VERSION 5.5 ;
NAMESCASESENSITIVE ON ;
BUSBITCHARS "[]" ;
DIVIDERCHAR "/" ;

PROPERTYDEFINITIONS
  LAYER routingPitch REAL ;
END PROPERTYDEFINITIONS

UNITS
  DATABASE MICRONS 1000 ;
END UNITS
MANUFACTURINGGRID 0.01 ;
LAYER POLY1
  TYPE MASTERSLICE ;
END POLY1

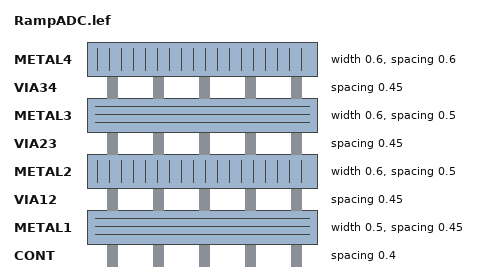
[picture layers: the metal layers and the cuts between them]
LAYER CONT
  TYPE CUT ;
  SPACING 0.4 ;
END CONT

LAYER METAL1
  TYPE ROUTING ;
  DIRECTION HORIZONTAL ;
  PITCH 0 ;
  WIDTH 0.5 ;
  SPACING 0.45 ;
  PROPERTY routingPitch 1.25 ;
END METAL1

LAYER VIA12
  TYPE CUT ;
  SPACING 0.45 ;
END VIA12

LAYER METAL2
  TYPE ROUTING ;
  DIRECTION VERTICAL ;
  PITCH 0 ;
  WIDTH 0.6 ;
  SPACING 0.5 ;
  PROPERTY routingPitch 1.4 ;
END METAL2

LAYER VIA23
  TYPE CUT ;
  SPACING 0.45 ;
END VIA23

LAYER METAL3
  TYPE ROUTING ;
  DIRECTION HORIZONTAL ;
  PITCH 0 ;
  WIDTH 0.6 ;
  SPACING 0.5 ;
  PROPERTY routingPitch 1.25 ;
END METAL3

LAYER VIA34
  TYPE CUT ;
  SPACING 0.45 ;
END VIA34

LAYER METAL4
  TYPE ROUTING ;
  DIRECTION VERTICAL ;
  PITCH 0 ;
  WIDTH 0.6 ;
  SPACING 0.6 ;
  PROPERTY routingPitch 1.4 ;
END METAL4

LAYER OVERLAP
  TYPE OVERLAP ;
END OVERLAP

VIARULE M4_M3 GENERATE
  LAYER METAL3 ;
    ENCLOSURE 0.2 0.2 ;
  LAYER METAL4 ;
    ENCLOSURE 0.15 0.15 ;
  LAYER VIA34 ;
    RECT -0.25 -0.25 0.25 0.25 ;
    SPACING 1 BY 1 ;
END M4_M3

VIARULE M3_M2 GENERATE
  LAYER METAL2 ;
    ENCLOSURE 0.2 0.2 ;
  LAYER METAL3 ;
    ENCLOSURE 0.15 0.15 ;
  LAYER VIA23 ;
    RECT -0.25 -0.25 0.25 0.25 ;
    SPACING 1 BY 1 ;
END M3_M2

VIARULE M2_M1 GENERATE
  LAYER METAL1 ;
    ENCLOSURE 0.2 0.2 ;
  LAYER METAL2 ;
    ENCLOSURE 0.15 0.15 ;
  LAYER VIA12 ;
    RECT -0.25 -0.25 0.25 0.25 ;
    SPACING 1 BY 1 ;
END M2_M1

VIARULE M1_POLY1 GENERATE
  LAYER POLY1 ;
    ENCLOSURE 0.2 0.2 ;
  LAYER METAL1 ;
    ENCLOSURE 0.15 0.15 ;
  LAYER CONT ;
    RECT -0.2 -0.2 0.2 0.2 ;
    SPACING 1 BY 1 ;
END M1_POLY1

VIA M1_POLY1
  LAYER CONT ;
    RECT -0.2 -0.2 0.2 0.2 ;
  LAYER POLY1 ;
    RECT -0.4 -0.4 0.4 0.4 ;
  LAYER METAL1 ;
    RECT -0.35 -0.35 0.35 0.35 ;
END M1_POLY1

VIA M2_M1
  LAYER VIA12 ;
    RECT -0.25 -0.25 0.25 0.25 ;
  LAYER METAL2 ;
    RECT -0.4 -0.4 0.4 0.4 ;
  LAYER METAL1 ;
    RECT -0.45 -0.45 0.45 0.45 ;
END M2_M1

VIA M3_M2
  LAYER VIA23 ;
    RECT -0.25 -0.25 0.25 0.25 ;
  LAYER METAL3 ;
    RECT -0.4 -0.4 0.4 0.4 ;
  LAYER METAL2 ;
    RECT -0.45 -0.45 0.45 0.45 ;
END M3_M2

VIA M4_M3
  LAYER VIA34 ;
    RECT -0.25 -0.25 0.25 0.25 ;
  LAYER METAL4 ;
    RECT -0.4 -0.4 0.4 0.4 ;
  LAYER METAL3 ;
    RECT -0.45 -0.45 0.45 0.45 ;
END M4_M3


MACRO TSMC350nm_Amplifier9T_FGBias
  PIN VD_P
    DIRECTION INOUT ;
    USE SIGNAL ;
    PORT
      LAYER METAL1 ;
        RECT 0.0 16.87 1.4 18.27 ;
    END
  END VD_P
  PIN Vout
    DIRECTION INOUT ;
    USE SIGNAL ;
    PORT
      LAYER METAL1 ;
        RECT 58.96 1.09 60.36 2.49 ;
    END
  END Vout
  PIN VIN_PLUS
    DIRECTION INOUT ;
    USE SIGNAL ;
    PORT
      LAYER METAL1 ;
        RECT 0.0 2.76 1.4 4.16 ;
    END
  END VIN_PLUS
  PIN VD_R
    DIRECTION INOUT ;
    USE SIGNAL ;
    PORT
      LAYER METAL1 ;
        RECT 0.0 11.17 1.4 12.57 ;
    END
  END VD_R
  PIN VIN_MINUS
    DIRECTION INOUT ;
    USE SIGNAL ;
    PORT
      LAYER METAL1 ;
        RECT 0.0 6.97 1.4 8.37 ;
    END
  END VIN_MINUS
  PIN GND_b
    DIRECTION INOUT ;
    USE SIGNAL ;
    PORT
      LAYER METAL2 ;
        RECT 51.59 0.0 52.99 1.4 ;
    END
  END GND_b
  PIN VPWR
    DIRECTION INOUT ;
    USE SIGNAL ;
    PORT
      LAYER METAL2 ;
        RECT 42.13 20.61 43.53 22.0 ;
    END
  END VPWR
  PIN Vsel_b
    DIRECTION INOUT ;
    USE SIGNAL ;
    PORT
      LAYER METAL2 ;
        RECT 0.66 0.0 2.06 1.4 ;
    END
  END Vsel_b
  PIN VINJ_b
    DIRECTION INOUT ;
    USE SIGNAL ;
    PORT
      LAYER METAL2 ;
        RECT 13.85 0.0 15.25 1.4 ;
    END
  END VINJ_b
  PIN Vg_b
    DIRECTION INOUT ;
    USE SIGNAL ;
    PORT
      LAYER METAL2 ;
        RECT 9.06 0.0 10.46 1.4 ;
    END
  END Vg_b
  PIN PROG_b
    DIRECTION INOUT ;
    USE SIGNAL ;
    PORT
      LAYER METAL2 ;
        RECT 6.26 0.0 7.66 1.4 ;
    END
  END PROG_b
  PIN VTUN_b
    DIRECTION INOUT ;
    USE SIGNAL ;
    PORT
      LAYER METAL2 ;
        RECT 3.46 0.0 4.86 1.4 ;
    END
  END VTUN_b
  PIN PROG
    DIRECTION INOUT ;
    USE SIGNAL ;
    PORT
      LAYER METAL2 ;
        RECT 6.26 20.6 7.66 22.0 ;
    END
  END PROG
  PIN VINJ
    DIRECTION INOUT ;
    USE SIGNAL ;
    PORT
      LAYER METAL2 ;
        RECT 13.85 20.6 15.25 22.0 ;
    END
  END VINJ
  PIN Vg
    DIRECTION INOUT ;
    USE SIGNAL ;
    PORT
      LAYER METAL2 ;
        RECT 9.06 20.6 10.46 22.0 ;
    END
  END Vg
  PIN VTUN
    DIRECTION INOUT ;
    USE SIGNAL ;
    PORT
      LAYER METAL2 ;
        RECT 3.46 20.6 4.86 22.0 ;
    END
  END VTUN
  PIN Vsel
    DIRECTION INOUT ;
    USE SIGNAL ;
    PORT
      LAYER METAL2 ;
        RECT 0.66 20.6 2.06 22.0 ;
    END
  END Vsel
  PIN GND
    DIRECTION INOUT ;
    USE SIGNAL ;
    PORT
      LAYER METAL2 ;
        RECT 51.59 20.6 52.99 22.0 ;
    END
  END GND
  PIN VPWR_b
    DIRECTION INOUT ;
    USE SIGNAL ;
    PORT
      LAYER METAL2 ;
        RECT 42.13 0.01 43.53 1.4 ;
    END
  END VPWR_b
END TSMC350nm_Amplifier9T_FGBias

MACRO TGate_DT
  PIN SELA
    DIRECTION INOUT ;
    USE SIGNAL ;
    PORT
      LAYER METAL1 ;
        RECT 0.0 13.5 1.4 14.9 ;
    END
  END SELA
  PIN C
    DIRECTION INOUT ;
    USE SIGNAL ;
    PORT
      LAYER METAL1 ;
        RECT 0.0 6.78 1.4 8.18 ;
    END
  END C
  PIN B
    DIRECTION INOUT ;
    USE SIGNAL ;
    PORT
      LAYER METAL1 ;
        RECT 7.18 9.11 8.58 10.51 ;
    END
  END B
  PIN A
    DIRECTION INOUT ;
    USE SIGNAL ;
    PORT
      LAYER METAL1 ;
        RECT 7.18 14.37 8.58 15.77 ;
    END
  END A
  PIN VDD_b
    DIRECTION INOUT ;
    USE SIGNAL ;
    PORT
      LAYER METAL2 ;
        RECT 4.07 0.0 5.47 1.4 ;
    END
  END VDD_b
  PIN GND_b
    DIRECTION INOUT ;
    USE SIGNAL ;
    PORT
      LAYER METAL2 ;
        RECT 1.82 0.0 3.22 1.4 ;
    END
  END GND_b
  PIN GND
    DIRECTION INOUT ;
    USE SIGNAL ;
    PORT
      LAYER METAL2 ;
        RECT 1.82 20.6 3.22 22.0 ;
    END
  END GND
  PIN VDD
    DIRECTION INOUT ;
    USE SIGNAL ;
    PORT
      LAYER METAL2 ;
        RECT 4.07 20.6 5.47 22.0 ;
    END
  END VDD
END TGate_DT

MACRO RippleCounter
  PIN GND_L
    DIRECTION INOUT ;
    USE SIGNAL ;
    PORT
      LAYER METAL1 ;
        RECT 0.0 4.39 1.18 6.69 ;
    END
  END GND_L
  PIN GND
    DIRECTION INOUT ;
    USE SIGNAL ;
    PORT
      LAYER METAL1 ;
        RECT 35.5 4.39 36.68 6.69 ;
    END
  END GND
  PIN VDD
    DIRECTION INOUT ;
    USE SIGNAL ;
    PORT
      LAYER METAL1 ;
        RECT 35.35 14.59 36.68 16.89 ;
    END
  END VDD
  PIN RST
    DIRECTION INOUT ;
    USE SIGNAL ;
    PORT
      LAYER METAL1 ;
        RECT 35.28 1.34 36.68 2.74 ;
    END
  END RST
  PIN VDD_L
    DIRECTION INOUT ;
    USE SIGNAL ;
    PORT
      LAYER METAL1 ;
        RECT 0.0 14.59 1.33 16.89 ;
    END
  END VDD_L
  PIN RST_L
    DIRECTION INOUT ;
    USE SIGNAL ;
    PORT
      LAYER METAL1 ;
        RECT 0.0 1.34 1.4 2.74 ;
    END
  END RST_L
  PIN CLK
    DIRECTION INOUT ;
    USE SIGNAL ;
    PORT
      LAYER METAL1 ;
        RECT 0.0 8.44 1.4 9.84 ;
    END
  END CLK
  PIN Count
    DIRECTION INOUT ;
    USE SIGNAL ;
    PORT
      LAYER METAL2 ;
        RECT 33.1 20.6 34.5 22.0 ;
    END
  END Count
  PIN Count_B
    DIRECTION INOUT ;
    USE SIGNAL ;
    PORT
      LAYER METAL2 ;
        RECT 33.1 0.0 34.5 1.4 ;
    END
  END Count_B
END RippleCounter

MACRO Capacitor_80ff
  PIN Bot
    DIRECTION INOUT ;
    USE SIGNAL ;
    PORT
      LAYER METAL1 ;
        RECT 20.21 10.47 21.31 12.17 ;
    END
  END Bot
  PIN Top
    DIRECTION INOUT ;
    USE SIGNAL ;
    PORT
      LAYER METAL1 ;
        RECT 0.0 10.48 1.16 12.17 ;
    END
  END Top
END Capacitor_80ff

END LIBRARY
